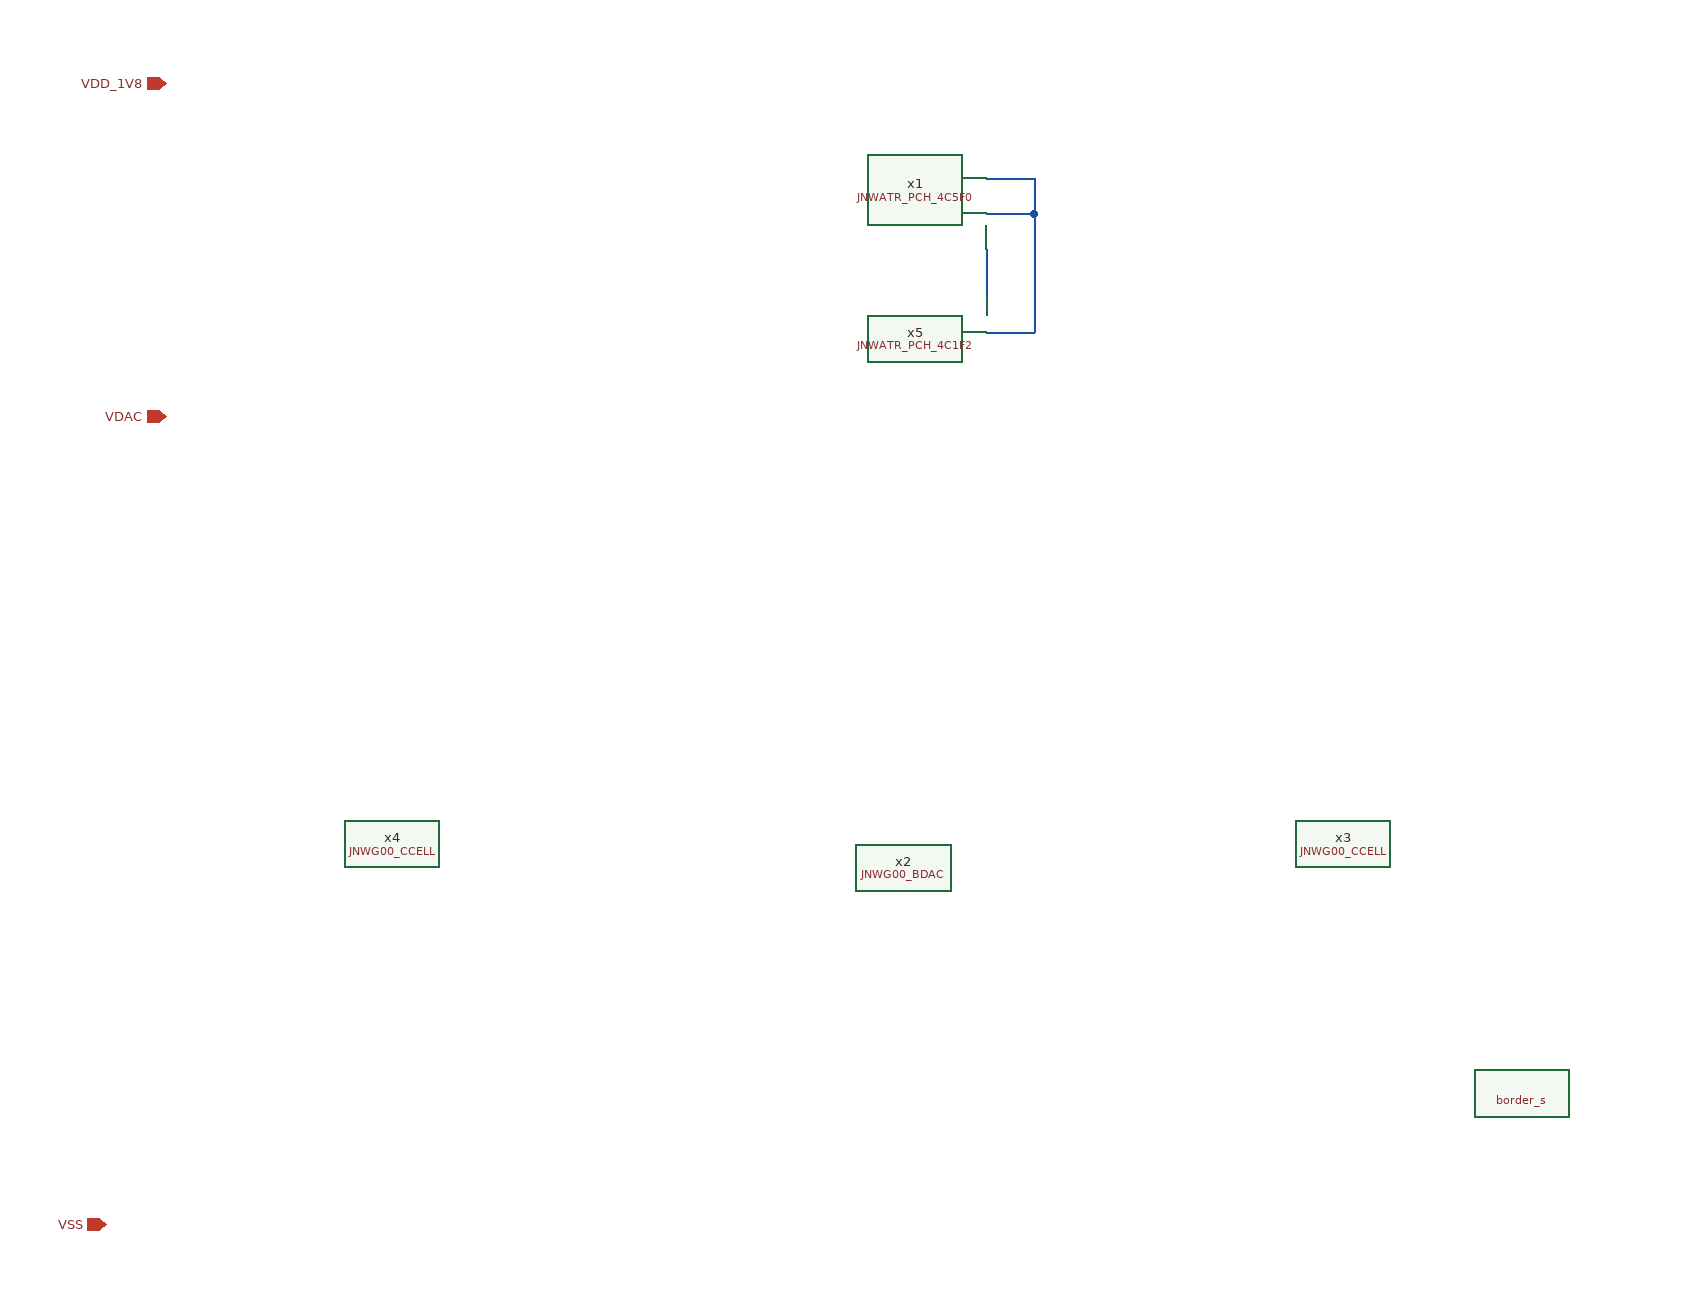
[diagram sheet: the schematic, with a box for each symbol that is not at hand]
v {xschem version=3.4.5 file_version=1.2
}
G {}
K {}
V {}
S {}
E {}
N 800 -910 840 -910 {
lab=#net1}
N 840 -940 840 -910 {
lab=#net1}
N 800 -940 840 -940 {
lab=#net1}
N 800 -880 800 -840 {
lab=#net2}
N 800 -810 840 -810 {
lab=#net1}
N 840 -910 840 -810 {
lab=#net1}
C {devices/ipin.sym} 110 -1020 0 0 {name=p1 lab=VDD_1V8}
C {devices/ipin.sym} 60 -60 0 0 {name=p2 lab=VSS}
C {cborder/border_s.sym} 1250 -170 0 0 {user="Carsten Wulff" company="Carsten Wulff Software"
lab=PWRUP_1V8}
C {devices/ipin.sym} 110 -740 0 0 {name=p3 lab=VDAC}
C {JNW_ATR_SKY130NM/JNWATR_PCH_4C5F0.sym} 760 -910 0 0 {name=x1 }
C {JNW_GR00_SKY130NM/JNWG00_BDAC.sym} 730 -360 0 0 {name=x2}
C {JNW_GR00_SKY130NM/JNWG00_CCELL.sym} 1100 -380 0 0 {name=x3}
C {JNW_GR00_SKY130NM/JNWG00_CCELL.sym} 300 -380 0 0 {name=x4}
C {JNW_ATR_SKY130NM/JNWATR_PCH_4C1F2.sym} 760 -810 0 0 {name=x5 }
